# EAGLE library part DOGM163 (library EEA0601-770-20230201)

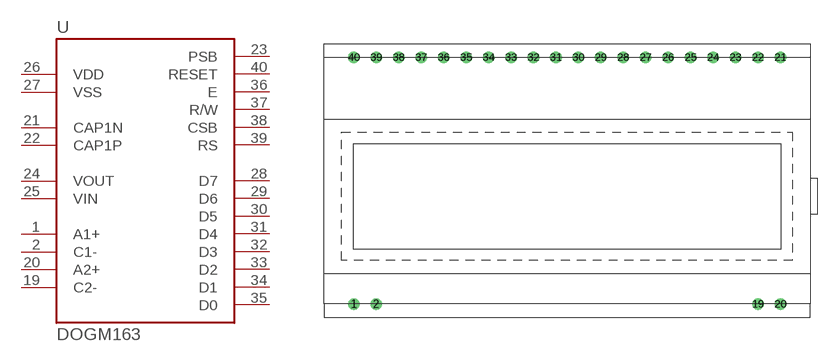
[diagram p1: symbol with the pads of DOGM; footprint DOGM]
Designator prefix U

## DOGM163  [DOGM]
1  A1+
2  C1-
19  C2-
20  A2+
21  CAP1N
22  CAP1P
23  PSB
24  VOUT
25  VIN
26  VDD
27  VSS
28  D7
29  D6
30  D5
31  D4
32  D3
33  D2
34  D1
35  D0
36  E
37  R/W
38  CSB
39  RS
40  RESET

## Footprint DOGM (pad centres in mm)
drill 0.8: 1 -24.13,-12.7; 2 -21.59,-12.7; 19 21.59,-12.7; 20 24.13,-12.7; 21 24.13,15.24; 22 21.59,15.24; 23 19.05,15.24; 24 16.51,15.24; 25 13.97,15.24; 26 11.43,15.24; 27 8.89,15.24; 28 6.35,15.24; 29 3.81,15.24; 30 1.27,15.24; 31 -1.27,15.24; 32 -3.81,15.24; 33 -6.35,15.24; 34 -8.89,15.24; 35 -11.43,15.24; 36 -13.97,15.24; 37 -16.51,15.24; 38 -19.05,15.24; 39 -21.59,15.24; 40 -24.13,15.24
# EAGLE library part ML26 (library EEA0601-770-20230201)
HARTING

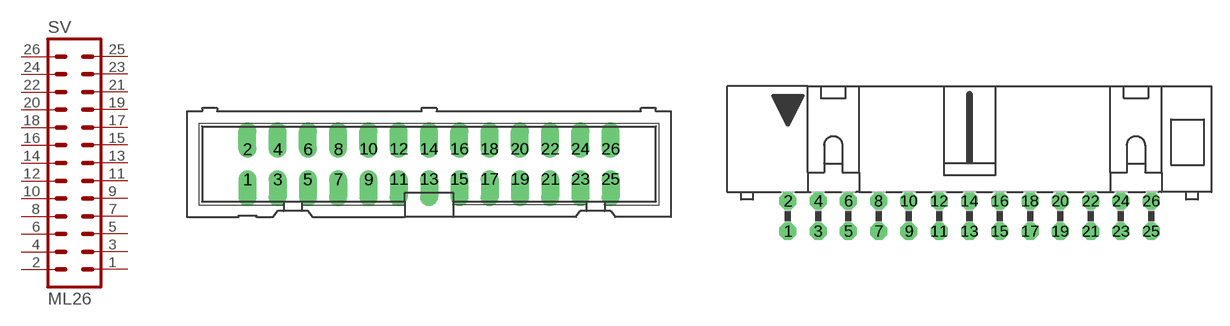
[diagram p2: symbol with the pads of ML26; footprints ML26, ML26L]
Designator prefix SV

## ML26 (OC_FARNELL: unknown; OC_NEWARK: unknown)  [ML26]
1  1  pas
2  2  pas
3  3  pas
4  4  pas
5  5  pas
6  6  pas
7  7  pas
8  8  pas
9  9  pas
10  10  pas
11  11  pas
12  12  pas
13  13  pas
14  14  pas
15  15  pas
16  16  pas
17  17  pas
18  18  pas
19  19  pas
20  20  pas
21  21  pas
22  22  pas
23  23  pas
24  24  pas
25  25  pas
26  26  pas

## ML26L (OC_FARNELL: unknown; OC_NEWARK: unknown)  [ML26L]
Pads as for ML26

## Footprint ML26 (pad centres in mm)
HARTING
drill 1 offset: 1 -15.24,-1.27; 2 -15.24,1.27; 3 -12.7,-1.27; 4 -12.7,1.27; 5 -10.16,-1.27; 6 -10.16,1.27; 7 -7.62,-1.27; 8 -7.62,1.27; 9 -5.08,-1.27; 10 -5.08,1.27; 11 -2.54,-1.27; 12 -2.54,1.27; 13 0,-1.27; 14 0,1.27; 15 2.54,-1.27; 16 2.54,1.27; 17 5.08,-1.27; 18 5.08,1.27; 19 7.62,-1.27; 20 7.62,1.27; 21 10.16,-1.27; 22 10.16,1.27; 23 12.7,-1.27; 24 12.7,1.27; 25 15.24,-1.27; 26 15.24,1.27

## Footprint ML26L (pad centres in mm)
HARTING
drill 0.914 octagon: 1 -15.24,-1.27; 2 -15.24,1.27; 3 -12.7,-1.27; 4 -12.7,1.27; 5 -10.16,-1.27; 6 -10.16,1.27; 7 -7.62,-1.27; 8 -7.62,1.27; 9 -5.08,-1.27; 10 -5.08,1.27; 11 -2.54,-1.27; 12 -2.54,1.27; 13 0,-1.27; 14 0,1.27; 15 2.54,-1.27; 16 2.54,1.27; 17 5.08,-1.27; 18 5.08,1.27; 19 7.62,-1.27; 20 7.62,1.27; 21 10.16,-1.27; 22 10.16,1.27; 23 12.7,-1.27; 24 12.7,1.27; 25 15.24,-1.27; 26 15.24,1.27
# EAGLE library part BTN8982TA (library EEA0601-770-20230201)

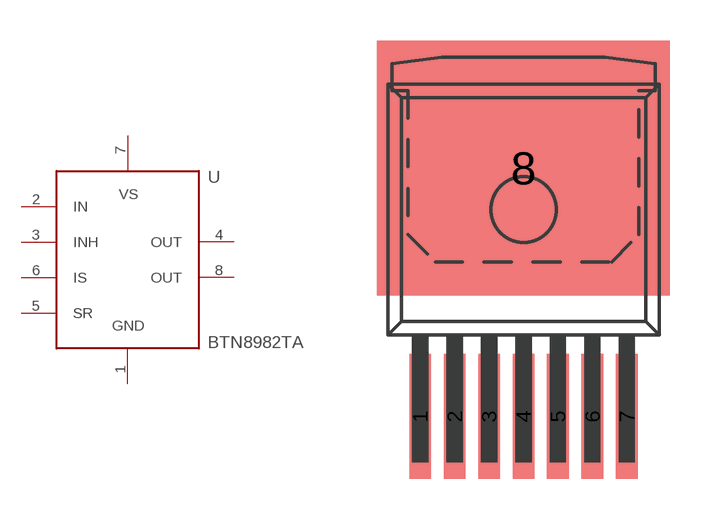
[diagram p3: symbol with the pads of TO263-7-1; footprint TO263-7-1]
Designator prefix U

## BTN8982TA  [TO263-7-1]
1  GND
2  IN
3  INH
4  OUT
5  SR
6  IS
7  VS
8  OUT

## Footprint TO263-7-1 (pad centres in mm)
smd 0.8 x 4.6: 1 -3.81,0; 2 -2.54,0; 3 -1.27,0; 4 0,0; 5 1.27,0; 6 2.54,0; 7 3.81,0
smd 10.8 x 9.4: 8 0,9.15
